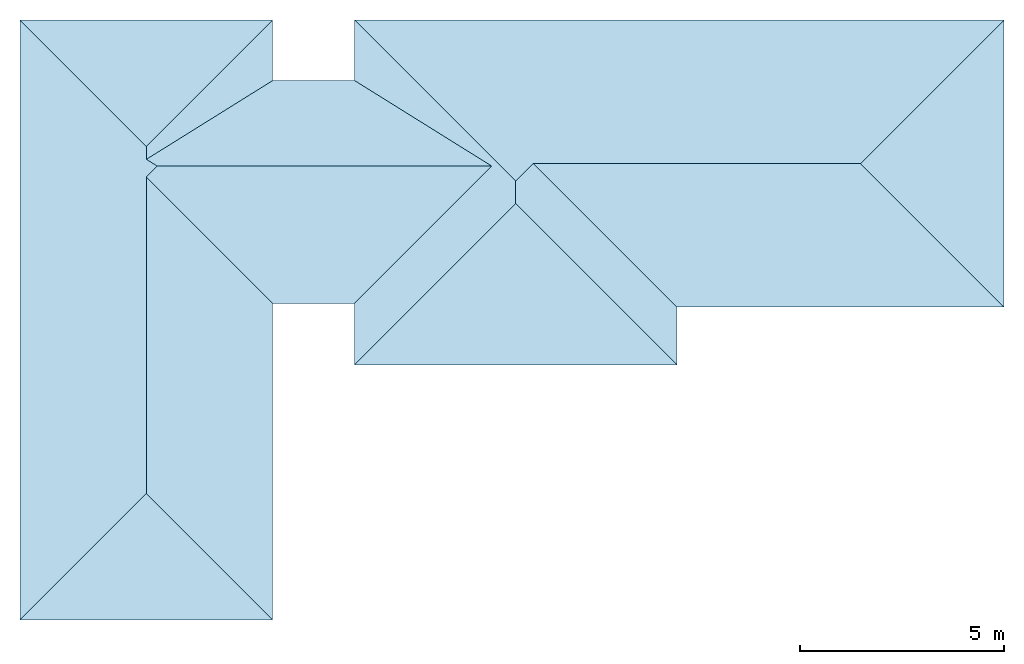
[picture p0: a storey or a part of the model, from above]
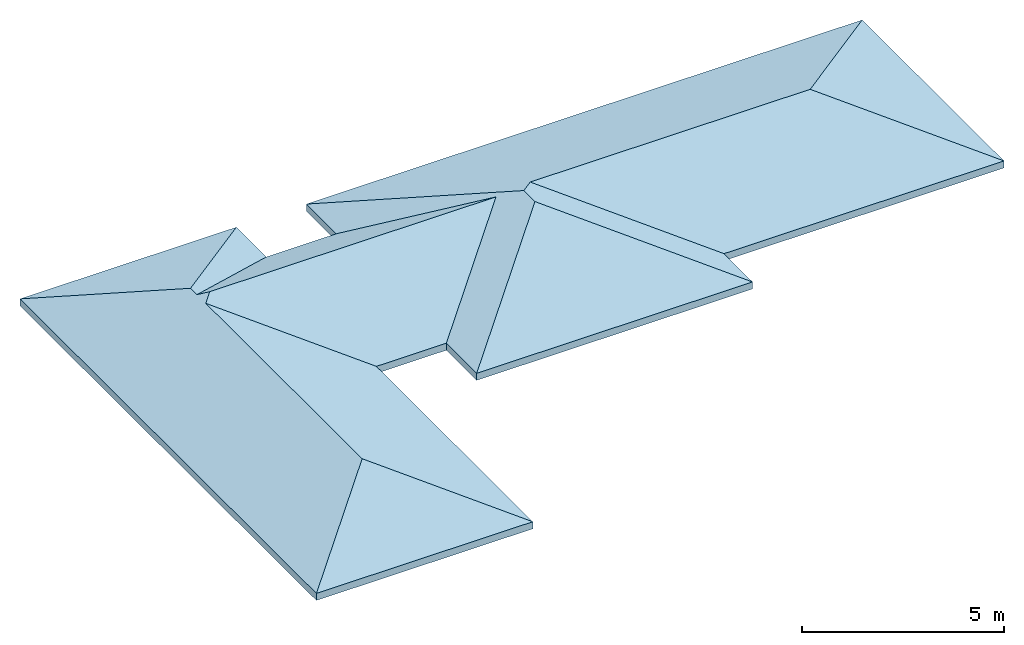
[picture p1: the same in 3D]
Properties of the parts of a building model (IFC2X3)

# File
Description: ViewDefinition [CoordinationView_V2.0]
File name: 0001
Time: 2022-12-05T09:21:00
Written by: The EXPRESS Data Manager Version 5.02.0100.07 : 28 Aug 2013
Made in: 20170223_1515(x64) - Exporter 18.0.0.420 - Alternate UI 18.0.0.420
Comment: STEP Physical File produced by: The EXPRESS Data Manager Version 5.02.0100.07 : 28 Aug 2013 * Module: EDMstepFileFactory/EDMstandAlone * Creation date: Mon Dec 05 09:21:00 2022 * Host: DESKTOP-B82V1SU * Database: C:\Users\MBF6C~1.MAS\AppData\Local\Temp\{A3475775-FA73-497D-B58A-869B8FA0B5F3}\ifc * Database version: 5507 * Database creation date: Mon Dec 05 09:20:54 2022 * Schema: IFC2X3 * Model: DataRepository.ifc * Model creation date: Mon Dec 05 09:20:54 2022 * Header model: DataRepository.ifc_HeaderModel * Header model creation date: Mon Dec 05 09:20:54 2022 * EDMuser: sdai-user * EDMgroup: sdai-group * License ID and type: 5605 : Permanent license. Expiry date: * EDMstepFileFactory options: 020000

# IfcProject, 0001
LongName: Nom du projet; Phase: Etat du projet

# IfcSite, Default
RefLatitude: 48, 51, 23, 999633; RefLongitude: 2, 21, 3, 553905; RefElevation: 0 m

# IfcBuilding
Pset_BuildingCommon - NumberOfStoreys: 3

# IfcBuildingStorey (3)
Name | LongName | Elevation (m)
1 - Fondations | 1 - Fondations | -1.43
2 - Rez de Chaussée | 2 - Rez de Chaussée | -1.94916e-14
3 - Combles | 3 - Combles | 2.67

# IfcSpace (12)
In: 2 - Rez de Chaussée
InteriorOrExteriorSpace: INTERNAL
Name | LongName | Reference
1 | Chambre 1 | Chambre 1 1
2 | Chambre 2 | Chambre 2 2
3 | SdB. | SdB. 3
4 | Sd'E. | Sd'E. 4
5 | Garage | Garage 5
6 | Cellier | Cellier 6
7 | W.C. | W.C. 7
8 | Salon/Séjour | Salon/Séjour 8
9 | Entrée | Entrée 9
10 | Dégt | Dégt 10
11 | Chambre 3 | Chambre 3 11
12 | Dressing | Dressing 12

# IfcBeam: Poutre rectangulaire - Béton:200 x 300 mm (4)
In: 1 - Fondations
Type - PredefinedType: BEAM
Material: Béton - Béton coulé sur place
Pset_BeamCommon - IsExternal: no; LoadBearing: yes; Reference: 200 x 300 mm; Slope: 0 deg
Name (Poutre rectangulaire - Béton:200 x 300 mm:...) | Span (m)
445510 | 23.22
445639 | 5.34
445669 | 2.84
445717 | 5.34

# IfcColumn: 800 x 200 (6)
In: 1 - Fondations
Type - ElementType: 800 x 200; PredefinedType: COLUMN; Material: Maçonnerie - Béton coulé sur place
Pset_ColumnCommon - IsExternal: no; LoadBearing: yes; Reference: 800 x 200
Name (Béton - Rectangulaire - Poteau:800 x 200:...)
443375
443681
443725
443775
443833
443899

# IfcCovering: Plafond composé:45_CEI_plafond_Siniat_geluidsisolatieverbeterend_plafond_zonder_naden, Plafond composé:45_CEI_plafond_Siniat_geluidsisolatieverbeterend_plafond_zonder_naden:447181
In: 2 - Rez de Chaussée
Classification: 45.11 (Uniformat); Material: 45_isolatie_minerale-wol_40mm 0.04 m, 45_metaal_profiel_Siniat_Veerrail 0.016 m, 45_gipskartonplaat_Siniat_Standaard_A_12.5mm 0.0125 m
Pset_CoveringCommon - Reference: 45_CEI_plafond_Siniat_geluidsisolatieverbeterend_plafond_zonder_naden; FireRating: n.v.t.; Finish: 45_gipskartonplaat_Siniat_Standaard_A_12.5mm;; TotalThickness: 0.0685 m
Pset_ManufacturerTypeInformation - Manufacturer: Siniat BV

# IfcCovering: Plafond composé:45_CEI_plafond_Siniat_verlaagd_plafond_direct_bevestigd_tegen_houten_balklaag_plaatnaden, Plafond composé:45_CEI_plafond_Siniat_verlaagd_plafond_direct_bevestigd_tegen_houten_balklaag_plaatnaden:448213
In: 2 - Rez de Chaussée
Classification: 45.11 (Uniformat); Material: 45_metaal_profiel_Siniat_CD60 0.027 m, 45_gipskartonplaat_Siniat_Standaard_A_9.5mm 0.0095 m
Pset_CoveringCommon - Reference: 45_CEI_plafond_Siniat_verlaagd_plafond_direct_bevestigd_tegen_houten_balklaag_plaatnaden; FireRating: n.v.t.; Finish: 45_gipskartonplaat_Siniat_Standaard_A_9.5mm;; TotalThickness: 0.0365 m
Pset_ManufacturerTypeInformation - Manufacturer: Siniat BV

# IfcDoor: 130 - 90 x 215 - Blanc, Avec panneau latéral:130 - 90 x 215 - Blanc:418100
In: 2 - Rez de Chaussée
Type - ParameterTakesPrecedence: no; Sizeable: no; Material: Peinture époxy - Blanc, Verre
OverallHeight: 2.225 m; OverallWidth: 1.41 m
Pset_DoorCommon - IsExternal: yes; Reference: 130 - 90 x 215 - Blanc

# IfcDoor: Garage sectionnelle (2)
In: 2 - Rez de Chaussée
Type - OperationType: ROLLINGUP; ParameterTakesPrecedence: no; Sizeable: no; Material: Plastique - Noir, Peinture - Grise, Verre
Type - Garage sectionnelle:Garage sectionnelle:397965 - PanelOperation: ROLLINGUP
OverallHeight: 3.03 m; OverallWidth: 2.145 m
Pset_DoorCommon - IsExternal: yes; Reference: Garage sectionnelle; ThermalTransmittance: 3.7021 kg/K/s3
Name (Garage sectionnelle:Garage sectionnelle:...)
397965
397992

# IfcDoor: Lisse - 0.90 m x 2.15 m, Ext. Simple:Lisse - 0.90 m x 2.15 m:432429
In: 2 - Rez de Chaussée
Type - OperationType: SINGLE_SWING_RIGHT; ParameterTakesPrecedence: no; Sizeable: no; Material: PVC - Blanc
Type - Ext. Simple:Lisse - 0.90 m x 2.15 m:432429 - PanelOperation: SWINGING
OverallHeight: 2.2 m; OverallWidth: 1 m
Pset_DoorCommon - IsExternal: yes; Reference: Lisse - 0.90 m x 2.15 m; ThermalTransmittance: 5.5617 kg/K/s3

# IfcDoor: PP Moulure cintrée (0.83 m x 2.04 m) (3)
In: 2 - Rez de Chaussée
Type - OperationType: SINGLE_SWING_LEFT; ParameterTakesPrecedence: no; Sizeable: no; Material: Finition Peinture - Blanc satiné, Bois - Panneau de porte, Bois - Cadre de porte
Type - Int. Simple - moulures:PP Moulure cintrée (0.83 m x 2.04 m):433741 - PanelOperation: SWINGING
OverallHeight: 2.075 m; OverallWidth: 0.9 m
Pset_DoorCommon - IsExternal: no; Reference: PP Moulure cintrée (0.83 m x 2.04 m); ThermalTransmittance: 3.7021 kg/K/s3
Name (Int. Simple - moulures:PP Moulure cintrée (0.83 m x 2.04 m):...)
433741
433771
433842

# IfcDoor: PP Moulure cintrée (0.83 m x 2.04 m) (4)
In: 2 - Rez de Chaussée
Type - OperationType: SINGLE_SWING_RIGHT; ParameterTakesPrecedence: no; Sizeable: no; Material: Finition Peinture - Blanc satiné, Bois - Panneau de porte, Bois - Cadre de porte
Type - Int. Simple - moulures:PP Moulure cintrée (0.83 m x 2.04 m):433652 - PanelOperation: SWINGING
OverallHeight: 2.075 m; OverallWidth: 0.9 m
Pset_DoorCommon - IsExternal: no; Reference: PP Moulure cintrée (0.83 m x 2.04 m); ThermalTransmittance: 3.7021 kg/K/s3
Name (Int. Simple - moulures:PP Moulure cintrée (0.83 m x 2.04 m):...)
433652
433707
433798
433877

# IfcDoor: PP Moulure cintrée (0.83 m x 2.04 m), Int. Simple - moulures:PP Moulure cintrée (0.83 m x 2.04 m):433907
In: 2 - Rez de Chaussée
Type - OperationType: SINGLE_SWING_RIGHT; ParameterTakesPrecedence: no; Sizeable: no; Material: Finition Peinture - Blanc satiné, Bois - Panneau de porte, Bois - Cadre de porte
Type - Int. Simple - moulures:PP Moulure cintrée (0.83 m x 2.04 m):433907 - PanelOperation: SWINGING
OverallHeight: 2.075 m; OverallWidth: 0.9 m
Pset_DoorCommon - IsExternal: no; Reference: PP Moulure cintrée (0.83 m x 2.04 m); ThermalTransmittance: 3.7021 kg/K/s3

# IfcFooting: Semelle filante:Soubassement 15 cm/15 cm x 50 cm (15)
In: 1 - Fondations
PredefinedType: STRIP_FOOTING; Material: Maçonnerie - Béton
Name (Semelle filante:Soubassement 15 cm/15 cm x 50 cm:...)
440390
440403
440416
440429
440442
440451
440469
440482
440495
440508
440521
440534
440547
440556
440575

# IfcRoof: Toit de base:Toit - 200 mm:630, Toit de base:Toit - 200 mm:451730
In: 3 - Combles
Material: Toit par défaut
Pset_RoofCommon - IsExternal: yes; Reference: Toit - 200 mm; TotalArea: 239.259 m2; ProjectedArea: 224.149 m2

# IfcSlab: Base rectangulaire:100 x 50 x 50 (6)
In: 1 - Fondations
PredefinedType: BASESLAB; Material: Béton - Béton coulé sur place
Pset_SlabCommon - IsExternal: no; PitchAngle: 0 deg; Reference: 100 x 50 x 50
Name (Base rectangulaire:100 x 50 x 50:...)
444353
444574
444641
444714
445066
445235

# IfcSlab: Sol:54 - L'Enveloppe Métallique du Bâtiment - Plancher collaborant avec protection feu et/ou acoustique, Sol:54 - L'Enveloppe Métallique du Bâtiment - Plancher collaborant avec protection feu et/ou acoustique:437400
In: 2 - Rez de Chaussée
PredefinedType: FLOOR; Material: L'Enveloppe Métallique du Bâtiment- Béton coulé + Armature 0.1 m, L'Enveloppe Métallique du Bâtiment - Bac acier+Béton coulé 0.1 m, L'Enveloppe Métallique du Bâtiment-Isolation 0.06 m
Pset_SlabCommon - IsExternal: no; Reference: 54 - L'Enveloppe Métallique du Bâtiment - Plancher collaborant avec protection feu et/ou acoustique; LoadBearing: yes; PitchAngle: 0 deg
Pset_ManufacturerTypeInformation - Manufacturer: L'Enveloppe Métallique du Bâtiment

# IfcSlab: Sol:Carrelage 1 + Chape liquide 4 (8)
In: 2 - Rez de Chaussée
PredefinedType: FLOOR; Material: Dalle, carrelage 25 x 25 0.01 m, Dalle, chape 0.04 m
Pset_SlabCommon - LoadBearing: no; IsExternal: no; Reference: Carrelage 1 + Chape liquide 4; ThermalTransmittance: 20.92 kg/K/s3
Name (Sol:Carrelage 1 + Chape liquide 4:...)
448275
448275:2
448275:3
448275:4
448275:5
449841
449841:2
449841:3

# IfcSlab: Sol:Plancher poutrelles hourdis - 16+10 (2)
In: 2 - Rez de Chaussée
PredefinedType: FLOOR; Material: Béton, coulé sur place 0.1 m, Fondations filantes 0.16 m
Pset_SlabCommon - IsExternal: no; LoadBearing: yes; PitchAngle: 0 deg; Reference: Plancher poutrelles hourdis - 16+10; ThermalTransmittance: 10.46 kg/K/s3
Name (Sol:Plancher poutrelles hourdis - 16+10:...)
438214
438599

# IfcWallStandardCase: Mur de base:BBM 20 cm x 50 cm x 20 cm, Mur de base:BBM 20 cm x 50 cm x 20 cm:438538
In: 1 - Fondations
Type - PredefinedType: STANDARD; Material: Blocs béton manufacturés 0.2 m
Pset_WallCommon - IsExternal: yes; ExtendToStructure: yes; LoadBearing: yes; Reference: BBM 20 cm x 50 cm x 20 cm; ThermalTransmittance: 6.5 kg/K/s3

# IfcWallStandardCase: Mur de base:CLOISON KMA 22 120/48 - 4KS13 - 56DB - EI60 - 2,8M - MONTANT DOUBLE - ENTRAXE 600, Mur de base:CLOISON KMA 22 120/48 - 4KS13 - 56DB - EI60 - 2,8M - MONTANT DOUBLE - ENTRAXE 600:396631
In: 2 - Rez de Chaussée
Type - PredefinedType: STANDARD; Material: Plâtre 0.01 m, Mur par défaut 0.1 m, Plâtre 0.01 m
Pset_WallCommon - LoadBearing: no; ExtendToStructure: no; IsExternal: no; Reference: CLOISON KMA 22 120/48 - 4KS13 - 56DB - EI60 - 2,8M - MONTANT DOUBLE - ENTRAXE 600; ThermalTransmittance: 25.5 kg/K/s3

# IfcWallStandardCase: Mur de base:Cloison distributive Placostil® 72/48 - 1x Placoplatre® BA 13 avec M 48 - EI30 - 33dB - max 3,45m (12)
In: 2 - Rez de Chaussée
Type - PredefinedType: STANDARD; Material: Mur par défaut 0.07 m
Pset_WallCommon - LoadBearing: no; ExtendToStructure: no; Reference: Cloison distributive Placostil® 72/48 - 1x Placoplatre® BA 13 avec M 48 - EI30 - 33dB - max 3,45m; IsExternal: no
Name (Mur de base:Cloison distributive Placostil® 72/48 - 1x Placoplatre® BA 13 avec M 48 - EI30 - 33dB - max 3,45m:...)
395277
395328
395399
395522
395570
395888
396005
396162
396284
396365
396433
434374

# IfcWallStandardCase: Mur de base:Isolant 10+1 vide 1 Parpaing 20 Enduit 2 (12)
In: 2 - Rez de Chaussée
Type - PredefinedType: STANDARD; Material: Maçonnerie - Enduit 0.02 m, Blocs béton manufacturés 0.2 m, TIFE, isolation extérieure 0.12 m
Pset_WallCommon - Reference: Isolant 10+1 vide 1 Parpaing 20 Enduit 2; LoadBearing: no; ExtendToStructure: no; IsExternal: yes; ThermalTransmittance: 0.186177 kg/K/s3
Name (Mur de base:Isolant 10+1 vide 1 Parpaing 20 Enduit 2:...)
394113
394150
394186
394248
394298
394500
394561
394607
394653
394720
394807
394901

# IfcWallStandardCase: Mur de base:Parpaing 20 Enduit 2 (3)
In: 2 - Rez de Chaussée
Type - PredefinedType: STANDARD; Material: Maçonnerie - Enduit 0.02 m, Blocs béton manufacturés 0.2 m
Pset_WallCommon - LoadBearing: no; ExtendToStructure: no; IsExternal: yes; Reference: Parpaing 20 Enduit 2; ThermalTransmittance: 6.5 kg/K/s3
Name (Mur de base:Parpaing 20 Enduit 2:...)
394354
394438
397330

# IfcWallStandardCase: Mur de base:Parpaing 20 Enduit bitumineux (14)
In: 1 - Fondations
Type - PredefinedType: STANDARD; Material: Blocs béton manufacturés 0.2 m
Pset_WallCommon - LoadBearing: no; IsExternal: yes; Reference: Parpaing 20 Enduit bitumineux; ExtendToStructure: yes; ThermalTransmittance: 6.5 kg/K/s3
Name (Mur de base:Parpaing 20 Enduit bitumineux:...)
434925
434926
434927
434928
434929
434930
434931
434932
434933
434934
434935
434936
434937
434938

# IfcWindow: 210 x 215 cm, PF-VR-2 Vantaux:210 x 215 cm:398087
In: 2 - Rez de Chaussée
Type - ParameterTakesPrecedence: no; Sizeable: no; Material: PVC - Blanc, Aluminium - Satiné, Béton - Ordinaire, Verre
OverallHeight: 2.40631 m; OverallWidth: 2.2 m
Pset_WindowCommon - IsExternal: yes; Reference: 210 x 215 cm

# IfcWindow: 80 x 215 cm VR (2)
In: 2 - Rez de Chaussée
Type - ParameterTakesPrecedence: no; Sizeable: no; Material: PVC - Blanc, Aluminium - Satiné, Verre
OverallHeight: 2.403 m; OverallWidth: 0.9 m
Pset_WindowCommon - IsExternal: yes; Reference: 80 x 215 cm VR
Name (PF-VR-1 Vantail:80 x 215 cm VR:...)
399175
406769

# IfcWindow: Baie couliss 240 x 215 cm VR (2)
In: 2 - Rez de Chaussée
Type - ParameterTakesPrecedence: no; Sizeable: no; Material: PVC - Blanc, Aluminium - Satiné, Béton - Ordinaire, Verre
OverallHeight: 2.40631 m; OverallWidth: 2.5 m
Pset_WindowCommon - IsExternal: yes; Reference: Baie couliss 240 x 215 cm VR
Name (PF-VR-2 Vantaux:Baie couliss 240 x 215 cm VR:...)
398246
398282

# IfcWindow: Fe 60 x 75 cm - Vitrage imprimé (4)
In: 2 - Rez de Chaussée
Type - OperationType: SINGLE_PANEL; ParameterTakesPrecedence: no; Sizeable: no; Material: Fenêtre - Poignée, Maçonnerie - Béton, Fenêtre - Vitrage, Fenêtre - Cadre
OverallHeight: 1.08 m; OverallWidth: 0.7 m
Pset_WindowCommon - IsExternal: yes; Reference: Fe 60 x 75 cm - Vitrage imprimé; ThermalTransmittance: 6.7069 kg/K/s3
Name (1 Vantail - Droit:Fe 60 x 75 cm - Vitrage imprimé:...)
398708
398803
398823
398887

# IfcWindow: Fe VR 120 x 125 cm (3)
In: 2 - Rez de Chaussée
Type - ParameterTakesPrecedence: no; Sizeable: no; Material: PVC - Blanc, Aluminium - Satiné, Béton - Ordinaire, Verre
OverallHeight: 1.55 m; OverallWidth: 1.3 m
Pset_WindowCommon - IsExternal: yes; Reference: Fe VR 120 x 125 cm
Name (VR-2 Vantaux:Fe VR 120 x 125 cm:...)
398464
398548
398578

# IfcWindow: Fe couliss VR 180x105cm, Rect 2 couliss+CVR+App:Fe couliss VR 180x105cm:406850
In: 2 - Rez de Chaussée
Type - ParameterTakesPrecedence: no; Sizeable: no; Material: PVC Blanc lames de volet roulant, PVC Blanc, Verre, Maçonnerie - Béton
OverallHeight: 1.83912 m; OverallWidth: 1.86 m
Pset_WindowCommon - IsExternal: yes; Reference: Fe couliss VR 180x105cm
